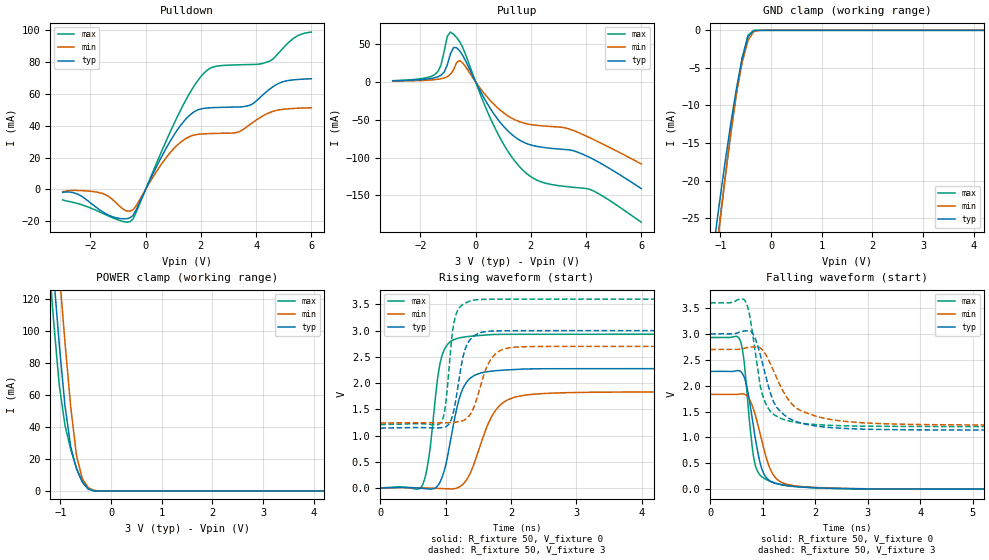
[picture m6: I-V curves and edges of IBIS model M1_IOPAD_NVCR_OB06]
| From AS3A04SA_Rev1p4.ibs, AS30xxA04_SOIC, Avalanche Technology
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[Model] M1_IOPAD_NVCR_OB06
Model_type I/O
Enable   Active-High
Vinl  =  0.9
Vinh  =  2.1
Vmeas =  1.5
Cref  =  30e-12
| Capacitance  typ   min   max
C_comp   3.872127e-12   3.590660e-12   4.190515e-12
| Variables   typ   min   max
[GND Clamp Reference]   0   0   0
[POWER Clamp Reference]   3   2.7   3.6
[Pulldown Reference]   0   0   0
[Pullup Reference]   3   2.7   3.6
[Temperature Range]   25   125   -40
[Voltage Range]   3   2.7   3.6
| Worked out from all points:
|   slope of the pulldown table from 0 to 0.45 V, typ, clamps not added: 27.9 ohm
|   slope of the pullup table from 0 to 0.45 V, typ, clamps not added: 14.9 ohm
|   GND clamp passes 1 mA (typ) near -0.46 V on its own axis
|   POWER clamp passes 1 mA (typ) near -0.42 V on its own axis
|   falling waveform, R_fixture 50, V_fixture 0: 20-80 % time 236ps typ, 304ps min, 174ps max; typ from 2.28 V to 0 V
|   falling waveform, R_fixture 50, V_fixture 3: 20-80 % time 382ps typ, 546ps min, 253ps max; typ from 3 V to 1.14 V
|   rising waveform, R_fixture 50, V_fixture 0: 20-80 % time 235ps typ, 350ps min, 166ps max; typ from 0 V to 2.28 V
|   rising waveform, R_fixture 50, V_fixture 3: 20-80 % time 164ps typ, 242ps min, 114ps max; typ from 1.14 V to 3 V
[GND Clamp]
| Voltage   I(typ)   I(min)   I(max)
-3V       -145.9mA   -153.7mA   -144.2mA
-1.138V   -29.07mA   -33.2mA    -32.68mA
-1.024V   -23.24mA   -26.38mA   -26.15mA
-910.3mV  -17.69mA   -19.83mA   -19.83mA
-796.6mV  -12.47mA   -13.74mA   -13.82mA
-682.8mV  -7.718mA   -8.413mA   -8.316mA
-569mV    -3.663mA   -4.215mA   -3.675mA
-455.2mV  -839.2uA   -1.36mA    -666.1uA
-341.4mV  -35.63uA   -163.9uA   -11.17uA
-113.8mV  -8.642nA   -411.9nA   -1.888nA
6V        0A         0A         0A
[POWER Clamp]
| Voltage   I(typ)   I(min)   I(max)
-3V       949.8mA    993.3mA    923.5mA
-1.252V   183.6mA    231.1mA    154mA
-1.138V   136.7mA    183.8mA    107.6mA
-1.024V   92.09mA    137.6mA    66.35mA
-910.3mV  53.33mA    93.06mA    41.06mA
-796.6mV  27.72mA    52.58mA    25.94mA
-682.8mV  13.75mA    22.15mA    14.29mA
-569mV    5.664mA    7.785mA    5.738mA
-455.2mV  1.446mA    2.116mA    1.305mA
-341.4mV  77.09uA    373.9uA    62.73uA
-227.6mV  1.148uA    21.11uA    332nA
6V        0A         0A         0A
[Pulldown]
| Voltage   I(typ)   I(min)   I(max)
-3V       -1.818mA   -1.414mA   -6.547mA
-2.39V    -3.494mA   -669uA     -9.164mA
-1.593V   -13.58mA   -2.334mA   -14.66mA
-569mV    -17.8mA    -13.62mA   -20.26mA
-341.4mV  -12.78mA   -10.3mA    -14.36mA
1.138V    37.05mA    27.66mA    45.21mA
2.069V    50.76mA    34.86mA    72.13mA
2.483V    51.35mA    35.13mA    76.98mA
3.745V    52.65mA    40.3mA     78.33mA
4.49V     62.91mA    48.21mA    80.49mA
5.359V    68.75mA    50.81mA    94.81mA
6V        69.43mA    51.26mA    98.69mA
[Pullup]
| Voltage   I(typ)   I(min)   I(max)
-3V       1.233mA    877.8uA    1.446mA
-1.479V   5.373mA    2.852mA    9.525mA
-1.252V   8.683mA    4.018mA    22.01mA
-1.138V   12.76mA    5.03mA     40.18mA
-910.3mV  37mA       9.541mA    65.62mA
-796.6mV  45.31mA    15.85mA    62.75mA
-569mV    40.45mA    27.87mA    52.57mA
724.1mV   -45.54mA   -31.9mA    -62.73mA
1.655V    -78.26mA   -53.49mA   -114.6mA
2.379V    -86.23mA   -58.05mA   -132.2mA
3.745V    -93.6mA    -67.38mA   -139.9mA
6V        -141mA     -108.5mA   -185.3mA
[Ramp]
dV/dt_r   1.36569/0.235041n  1.09954/0.350014n  1.75879/0.166379n
dV/dt_f   1.11466/0.381872n  0.876687/0.545945n  1.43365/0.253146n
R_load = 50
[Falling Waveform]
R_fixture = 50
V_fixture = 0
V_fixture_min = 0
V_fixture_max = 0
| Time   V(typ)   V(min)   V(max)
0s        2.276V     1.833V     2.931V
554.1ps   2.289V     1.838V     2.908V
626.6ps   2.209V     1.842V     2.606V
693ps     1.996V     1.809V     1.931V
801.9ps   1.342V     1.61V      787.8mV
880ps     855.4mV    1.351V     390.8mV
1.003ns   334.3mV    847.8mV    223.3mV
1.181ns   134.8mV    309.2mV    136.6mV
1.56ns    56.31mV    73.11mV    56.31mV
21.88ns   748.7nV    1.376uV    11.74uV
[Falling Waveform]
R_fixture = 50
V_fixture = 3
V_fixture_min = 2.7
V_fixture_max = 3.6
| Time   V(typ)   V(min)   V(max)
0s        3V         2.7V       3.6V
654.8ps   3.059V     2.729V     3.653V
737.2ps   3.06V      2.742V     3.421V
841.1ps   2.951V     2.749V     2.755V
956.6ps   2.58V      2.726V     1.976V
1.062ns   2.159V     2.593V     1.639V
1.276ns   1.567V     2.122V     1.4V
1.799ns   1.26V      1.488V     1.267V
3.916ns   1.146V     1.25V      1.212V
21.88ns   1.142V     1.239V     1.211V
[Rising Waveform]
R_fixture = 50
V_fixture = 0
V_fixture_min = 0
V_fixture_max = 0
| Time   V(typ)   V(min)   V(max)
0s        455.7nV    974.3nV    11.7uV
646.1ps   -3.297mV   7.37mV     61.69mV
745.3ps   -14.7mV    3.546mV    600.1mV
875.5ps   41.5mV     -3.001mV   2.072V
944.4ps   202.1mV    -6.768mV   2.525V
1.189ns   1.614V     11.34mV    2.854V
1.342ns   2.05V      202.5mV    2.888V
1.817ns   2.242V     1.561V     2.928V
2.464ns   2.274V     1.8V       2.93V
21.88ns   2.276V     1.833V     2.931V
[Rising Waveform]
R_fixture = 50
V_fixture = 3
V_fixture_min = 2.7
V_fixture_max = 3.6
| Time   V(typ)   V(min)   V(max)
0s        1.142V     1.239V     1.211V
928.5ps   1.15V      1.244V     1.248V
995.4ps   1.168V     1.244V     1.553V
1.099ns   1.352V     1.251V     2.914V
1.158ns   1.688V     1.258V     3.303V
1.29ns    2.611V     1.303V     3.517V
1.484ns   2.937V     1.734V     3.588V
1.741ns   2.992V     2.529V     3.598V
2.174ns   2.999V     2.692V     3.599V
21.88ns   3V         2.7V       3.6V
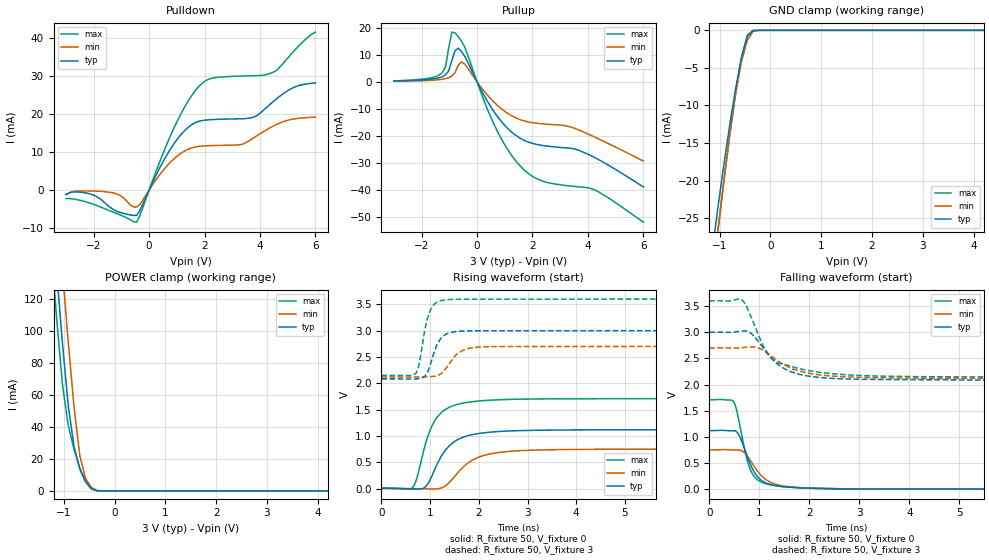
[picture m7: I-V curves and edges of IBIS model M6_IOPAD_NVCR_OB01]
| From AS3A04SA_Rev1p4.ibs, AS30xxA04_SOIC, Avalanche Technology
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[Model] M6_IOPAD_NVCR_OB01
Model_type I/O
Enable   Active-High
Vinl  =  0.9
Vinh  =  2.1
Vmeas =  1.5
Cref  =  30e-12
| Capacitance  typ   min   max
C_comp   3.872127e-12   3.590660e-12   4.190515e-12
| Variables   typ   min   max
[GND Clamp Reference]   0   0   0
[POWER Clamp Reference]   3   2.7   3.6
[Pulldown Reference]   0   0   0
[Pullup Reference]   3   2.7   3.6
[Temperature Range]   25   125   -40
[Voltage Range]   3   2.7   3.6
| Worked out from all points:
|   slope of the pulldown table from 0 to 0.45 V, typ, clamps not added: 66.9 ohm
|   slope of the pullup table from 0 to 0.45 V, typ, clamps not added: 53.1 ohm
|   GND clamp passes 1 mA (typ) near -0.46 V on its own axis
|   POWER clamp passes 1 mA (typ) near -0.42 V on its own axis
|   falling waveform, R_fixture 50, V_fixture 0: 20-80 % time 321ps typ, 404ps min, 255ps max; typ from 1.12 V to 0 V
|   falling waveform, R_fixture 50, V_fixture 3: 20-80 % time 599ps typ, 714ps min, 504ps max; typ from 3 V to 2.08 V
|   rising waveform, R_fixture 50, V_fixture 0: 20-80 % time 475ps typ, 578ps min, 386ps max; typ from 0 V to 1.12 V
|   rising waveform, R_fixture 50, V_fixture 3: 20-80 % time 221ps typ, 307ps min, 185ps max; typ from 2.08 V to 3 V
[GND Clamp]
| Voltage   I(typ)   I(min)   I(max)
-3V       -145.9mA   -153.7mA   -144.2mA
-1.138V   -29.07mA   -33.2mA    -32.68mA
-1.024V   -23.24mA   -26.38mA   -26.15mA
-910.3mV  -17.69mA   -19.83mA   -19.83mA
-796.6mV  -12.47mA   -13.74mA   -13.82mA
-682.8mV  -7.718mA   -8.413mA   -8.316mA
-569mV    -3.663mA   -4.215mA   -3.675mA
-455.2mV  -839.2uA   -1.36mA    -666.1uA
-341.4mV  -35.63uA   -163.9uA   -11.17uA
-113.8mV  -8.642nA   -411.9nA   -1.888nA
6V        0A         0A         0A
[POWER Clamp]
| Voltage   I(typ)   I(min)   I(max)
-3V       949.8mA    993.3mA    923.5mA
-1.252V   183.6mA    231.1mA    154mA
-1.138V   136.7mA    183.8mA    107.6mA
-1.024V   92.09mA    137.6mA    66.35mA
-910.3mV  53.33mA    93.06mA    41.06mA
-796.6mV  27.72mA    52.58mA    25.94mA
-682.8mV  13.75mA    22.15mA    14.29mA
-569mV    5.664mA    7.785mA    5.738mA
-455.2mV  1.446mA    2.116mA    1.305mA
-341.4mV  77.09uA    373.9uA    62.73uA
-227.6mV  1.148uA    21.11uA    332nA
6V        0A         0A         0A
[Pulldown]
| Voltage   I(typ)   I(min)   I(max)
-3V       -1.178mA   -1.235mA   -2.252mA
-2.162V   -950.8uA   -238uA     -3.362mA
-1.366V   -4.767mA   -675.5uA   -5.601mA
-455.2mV  -6.659mA   -4.469mA   -8.439mA
827.6mV   11.41mA    7.714mA    15.18mA
1.759V    17.96mA    11.42mA    26.89mA
2.276V    18.48mA    11.67mA    29.35mA
3.248V    18.68mA    11.86mA    29.88mA
3.745V    19.07mA    13.57mA    29.98mA
4.49V     23.28mA    16.82mA    30.94mA
5.234V    26.97mA    18.65mA    36.55mA
6V        28.1mA     19.13mA    41.44mA
[Pullup]
| Voltage   I(typ)   I(min)   I(max)
-3V       306.9uA    218.3uA    360.3uA
-1.366V   1.498mA    804.7uA    2.527mA
-1.138V   2.564mA    1.18mA     5.499mA
-1.024V   4.04mA     1.53mA     12.49mA
-910.3mV  7.819mA    2.112mA    18.38mA
-796.6mV  11.48mA    3.384mA    18.09mA
-455.2mV  9.605mA    6.652mA    13.03mA
620.7mV   -11.18mA   -7.609mA   -15.89mA
1.655V    -21.41mA   -14.32mA   -32.13mA
2.379V    -23.53mA   -15.54mA   -36.72mA
3.745V    -25.61mA   -18.1mA    -38.87mA
6V        -38.84mA   -29.27mA   -51.86mA
[Ramp]
dV/dt_r   0.671391/0.474616n  0.450443/0.578177n  1.02545/0.385509n
dV/dt_f   0.55145/0.59859n  0.348742/0.713857n  0.872156/0.50432n
R_load = 50
[Falling Waveform]
R_fixture = 50
V_fixture = 0
V_fixture_min = 0
V_fixture_max = 0
| Time   V(typ)   V(min)   V(max)
0s        1.119V     750.7mV    1.709V
473.4ps   1.118V     750mV      1.686V
533.2ps   1.106V     750.7mV    1.555V
593.2ps   1.034V     750.2mV    1.298V
728.9ps   703.6mV    668.5mV    653.8mV
863.5ps   386.6mV    484.9mV    288.7mV
1.084ns   142.2mV    217.9mV    117.2mV
1.528ns   42.92mV    54.51mV    43.77mV
3.632ns   1.461mV    2.02mV     1.096mV
21.88ns   384.8nV    1.042uV    8.699uV
[Falling Waveform]
R_fixture = 50
V_fixture = 3
V_fixture_min = 2.7
V_fixture_max = 3.6
| Time   V(typ)   V(min)   V(max)
0s        3V         2.7V       3.6V
657.7ps   3.026V     2.709V     3.615V
831.8ps   2.984V     2.72V      3.301V
1.084ns   2.691V     2.65V      2.73V
1.186ns   2.563V     2.583V     2.57V
1.324ns   2.424V     2.486V     2.441V
1.551ns   2.279V     2.351V     2.372V
1.808ns   2.194V     2.257V     2.302V
2.743ns   2.107V     2.147V     2.187V
21.88ns   2.081V     2.119V     2.146V
[Rising Waveform]
R_fixture = 50
V_fixture = 0
V_fixture_min = 0
V_fixture_max = 0
| Time   V(typ)   V(min)   V(max)
0s        324.6nV    979.6nV    8.69uV
624.3ps   -2.1mV     894.9uV    7.487mV
734.1ps   -6.735mV   -48.89uV   219.7mV
907.3ps   39.49mV    -2.876mV   860.6mV
1.128ns   434.2mV    -3.929mV   1.337V
1.475ns   879mV      201.2mV    1.575V
2.008ns   1.05V      601.2mV    1.666V
2.686ns   1.097V     712.4mV    1.696V
4.196ns   1.117V     746.6mV    1.708V
21.88ns   1.119V     750.7mV    1.709V
[Rising Waveform]
R_fixture = 50
V_fixture = 3
V_fixture_min = 2.7
V_fixture_max = 3.6
| Time   V(typ)   V(min)   V(max)
0s        2.081V     2.119V     2.146V
705ps     2.083V     2.12V      2.19V
773.5ps   2.089V     2.12V      2.37V
887.1ps   2.13V      2.12V      2.998V
1.012ns   2.382V     2.127V     3.402V
1.161ns   2.769V     2.152V     3.551V
1.364ns   2.948V     2.336V     3.59V
1.667ns   2.992V     2.624V     3.597V
2.253ns   2.999V     2.696V     3.599V
21.88ns   3V         2.7V       3.6V
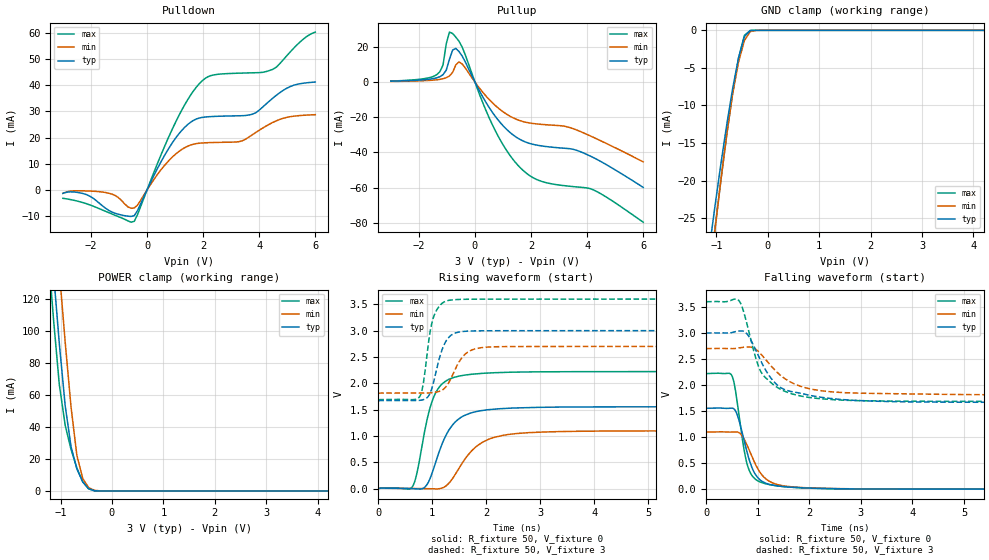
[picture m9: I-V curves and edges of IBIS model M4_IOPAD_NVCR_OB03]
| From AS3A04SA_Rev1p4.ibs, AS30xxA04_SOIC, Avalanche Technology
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[Model] M4_IOPAD_NVCR_OB03
Model_type I/O
Enable   Active-High
Vinl  =  0.9
Vinh  =  2.1
Vmeas =  1.5
Cref  =  30e-12
| Capacitance  typ   min   max
C_comp   3.872127e-12   3.590660e-12   4.190515e-12
| Variables   typ   min   max
[GND Clamp Reference]   0   0   0
[POWER Clamp Reference]   3   2.7   3.6
[Pulldown Reference]   0   0   0
[Pullup Reference]   3   2.7   3.6
[Temperature Range]   25   125   -40
[Voltage Range]   3   2.7   3.6
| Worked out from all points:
|   slope of the pulldown table from 0 to 0.45 V, typ, clamps not added: 46 ohm
|   slope of the pullup table from 0 to 0.45 V, typ, clamps not added: 34.5 ohm
|   GND clamp passes 1 mA (typ) near -0.46 V on its own axis
|   POWER clamp passes 1 mA (typ) near -0.42 V on its own axis
|   falling waveform, R_fixture 50, V_fixture 0: 20-80 % time 279ps typ, 355ps min, 219ps max; typ from 1.55 V to 0 V
|   falling waveform, R_fixture 50, V_fixture 3: 20-80 % time 543ps typ, 669ps min, 453ps max; typ from 3 V to 1.67 V
|   rising waveform, R_fixture 50, V_fixture 0: 20-80 % time 402ps typ, 532ps min, 297ps max; typ from 0 V to 1.55 V
|   rising waveform, R_fixture 50, V_fixture 3: 20-80 % time 219ps typ, 287ps min, 166ps max; typ from 1.67 V to 3 V
[GND Clamp]
| Voltage   I(typ)   I(min)   I(max)
-3V       -145.9mA   -153.7mA   -144.2mA
-1.138V   -29.07mA   -33.2mA    -32.68mA
-1.024V   -23.24mA   -26.38mA   -26.15mA
-910.3mV  -17.69mA   -19.83mA   -19.83mA
-796.6mV  -12.47mA   -13.74mA   -13.82mA
-682.8mV  -7.718mA   -8.413mA   -8.316mA
-569mV    -3.663mA   -4.215mA   -3.675mA
-455.2mV  -839.2uA   -1.36mA    -666.1uA
-341.4mV  -35.63uA   -163.9uA   -11.17uA
-113.8mV  -8.642nA   -411.9nA   -1.888nA
6V        0A         0A         0A
[POWER Clamp]
| Voltage   I(typ)   I(min)   I(max)
-3V       949.8mA    993.3mA    923.5mA
-1.252V   183.6mA    231.1mA    154mA
-1.138V   136.7mA    183.8mA    107.6mA
-1.024V   92.09mA    137.6mA    66.35mA
-910.3mV  53.33mA    93.06mA    41.06mA
-796.6mV  27.72mA    52.58mA    25.94mA
-682.8mV  13.75mA    22.15mA    14.29mA
-569mV    5.664mA    7.785mA    5.738mA
-455.2mV  1.446mA    2.116mA    1.305mA
-341.4mV  77.09uA    373.9uA    62.73uA
-227.6mV  1.148uA    21.11uA    332nA
6V        0A         0A         0A
[Pulldown]
| Voltage   I(typ)   I(min)   I(max)
-3V       -1.302mA   -1.27mA    -3.185mA
-2.162V   -1.762mA   -368.1uA   -5.24mA
-1.366V   -7.779mA   -1.22mA    -8.662mA
-455.2mV  -9.808mA   -6.881mA   -11.97mA
931mV     18.47mA    12.86mA    23.93mA
1.862V    27.49mA    17.86mA    40.59mA
2.379V    28.09mA    18.14mA    43.96mA
3.248V    28.34mA    18.4mA     44.61mA
3.745V    28.91mA    21.01mA    44.76mA
4.49V     35.12mA    25.83mA    46.12mA
5.11V     39.54mA    28.01mA    52.79mA
6V        41.23mA    28.76mA    60.32mA
[Pullup]
| Voltage   I(typ)   I(min)   I(max)
-3V       480.5uA    342.2uA    563.8uA
-1.366V   2.392mA    1.272mA    4.137mA
-1.138V   4.176mA    1.875mA    9.68mA
-910.3mV  12.91mA    3.392mA    28.39mA
-796.6mV  18.14mA    5.479mA    27.6mA
-455.2mV  14.74mA    10.29mA    19.83mA
620.7mV   -17.18mA   -11.77mA   -24.25mA
1.655V    -33.03mA   -22.19mA   -49.34mA
2.379V    -36.33mA   -24.08mA   -56.49mA
3.745V    -39.52mA   -28.03mA   -59.79mA
4.366V    -44.12mA   -32.49mA   -62.42mA
6V        -59.9mA    -45.37mA   -79.67mA
[Ramp]
dV/dt_r   0.931955/0.401817n  0.657846/0.531614n  1.33324/0.296908n
dV/dt_f   0.799473/0.543284n  0.533846/0.669445n  1.14844/0.452872n
R_load = 50
[Falling Waveform]
R_fixture = 50
V_fixture = 0
V_fixture_min = 0
V_fixture_max = 0
| Time   V(typ)   V(min)   V(max)
0s        1.553V     1.096V     2.222V
495.5ps   1.556V     1.096V     2.189V
543ps     1.539V     1.099V     2.038V
615.3ps   1.394V     1.095V     1.583V
731.8ps   952.6mV    971.5mV    780.2mV
838.4ps   555.3mV    743.6mV    354.5mV
949.5ps   291.5mV    492.9mV    196.4mV
1.107ns   137.6mV    245.4mV    116.8mV
1.489ns   50.53mV    65.65mV    50.77mV
21.88ns   478.9nV    1.117uV    10.18uV
[Falling Waveform]
R_fixture = 50
V_fixture = 3
V_fixture_min = 2.7
V_fixture_max = 3.6
| Time   V(typ)   V(min)   V(max)
0s        3V         2.7V       3.6V
625.8ps   3.037V     2.711V     3.633V
699.1ps   3.039V     2.723V     3.498V
813.3ps   2.956V     2.73V      3.087V
978.9ps   2.635V     2.675V     2.466V
1.092ns   2.4V       2.562V     2.205V
1.459ns   1.943V     2.174V     1.911V
2.195ns   1.77V      1.895V     1.738V
4.389ns   1.672V     1.824V     1.687V
21.88ns   1.668V     1.81V      1.686V
[Rising Waveform]
R_fixture = 50
V_fixture = 0
V_fixture_min = 0
V_fixture_max = 0
| Time   V(typ)   V(min)   V(max)
0s        382nV      969nV      10.07uV
614.8ps   -1.423mV   3.031mV    9.209mV
711ps     -7.837mV   1.452mV    263.7mV
872.8ps   33.79mV    -2.646mV   1.152V
1.07ns    516.4mV    -7.813mV   1.829V
1.361ns   1.187V     166.1mV    2.096V
1.693ns   1.428V     673mV      2.168V
2.267ns   1.517V     1.002V     2.205V
3.502ns   1.549V     1.085V     2.22V
21.88ns   1.553V     1.096V     2.222V
[Rising Waveform]
R_fixture = 50
V_fixture = 3
V_fixture_min = 2.7
V_fixture_max = 3.6
| Time   V(typ)   V(min)   V(max)
0s        1.668V     1.81V      1.686V
767.9ps   1.675V     1.812V     1.744V
837.4ps   1.689V     1.812V     2.007V
933.6ps   1.761V     1.815V     2.787V
1.032ns   2.045V     1.824V     3.278V
1.196ns   2.673V     1.877V     3.53V
1.389ns   2.938V     2.183V     3.587V
1.649ns   2.99V      2.585V     3.596V
2.153ns   2.998V     2.693V     3.599V
21.88ns   3V         2.7V       3.6V
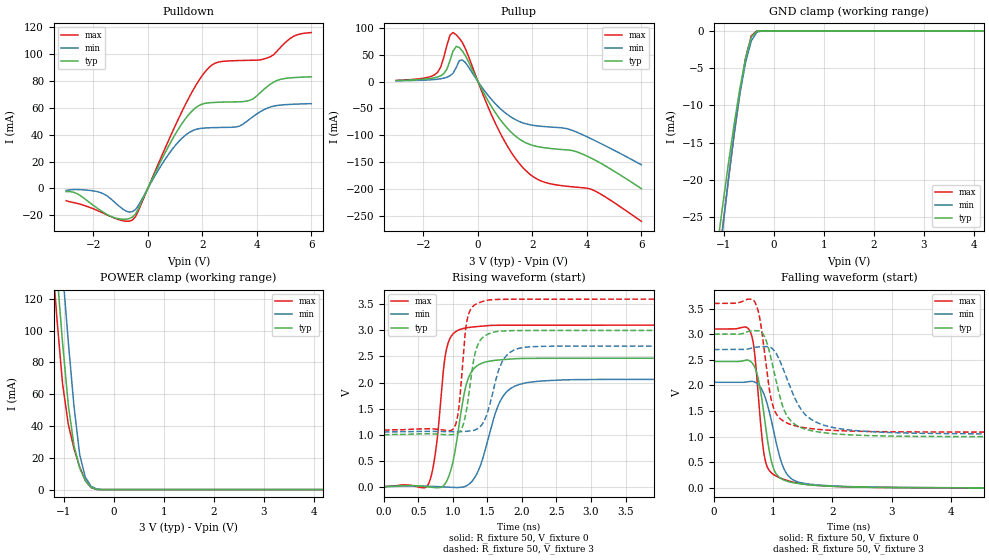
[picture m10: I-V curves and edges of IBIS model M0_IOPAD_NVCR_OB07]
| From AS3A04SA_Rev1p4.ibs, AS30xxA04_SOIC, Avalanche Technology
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[Model] M0_IOPAD_NVCR_OB07
Model_type I/O
Enable   Active-High
Vinl  =  0.9
Vinh  =  2.1
Vmeas =  1.5
Cref  =  30e-12
| Capacitance  typ   min   max
C_comp   3.872127e-12   3.590660e-12   4.190515e-12
| Variables   typ   min   max
[GND Clamp Reference]   0   0   0
[POWER Clamp Reference]   3   2.7   3.6
[Pulldown Reference]   0   0   0
[Pullup Reference]   3   2.7   3.6
[Temperature Range]   25   125   -40
[Voltage Range]   3   2.7   3.6
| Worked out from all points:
|   slope of the pulldown table from 0 to 0.45 V, typ, clamps not added: 23.6 ohm
|   slope of the pullup table from 0 to 0.45 V, typ, clamps not added: 10.6 ohm
|   GND clamp passes 1 mA (typ) near -0.46 V on its own axis
|   POWER clamp passes 1 mA (typ) near -0.42 V on its own axis
|   falling waveform, R_fixture 50, V_fixture 0: 20-80 % time 201ps typ, 270ps min, 152ps max; typ from 2.47 V to 0 V
|   falling waveform, R_fixture 50, V_fixture 3: 20-80 % time 290ps typ, 437ps min, 196ps max; typ from 3 V to 0.999 V
|   rising waveform, R_fixture 50, V_fixture 0: 20-80 % time 194ps typ, 288ps min, 142ps max; typ from 0 V to 2.47 V
|   rising waveform, R_fixture 50, V_fixture 3: 20-80 % time 142ps typ, 214ps min, 100ps max; typ from 0.999 V to 3 V
[GND Clamp]
| Voltage   I(typ)   I(min)   I(max)
-3V       -145.9mA   -153.7mA   -144.2mA
-1.138V   -29.07mA   -33.2mA    -32.68mA
-1.024V   -23.24mA   -26.38mA   -26.15mA
-910.3mV  -17.69mA   -19.83mA   -19.83mA
-796.6mV  -12.47mA   -13.74mA   -13.82mA
-682.8mV  -7.718mA   -8.413mA   -8.316mA
-569mV    -3.663mA   -4.215mA   -3.675mA
-455.2mV  -839.2uA   -1.36mA    -666.1uA
-341.4mV  -35.63uA   -163.9uA   -11.17uA
-113.8mV  -8.642nA   -411.9nA   -1.888nA
6V        0A         0A         0A
[POWER Clamp]
| Voltage   I(typ)   I(min)   I(max)
-3V       949.8mA    993.3mA    923.5mA
-1.252V   183.6mA    231.1mA    154mA
-1.138V   136.7mA    183.8mA    107.6mA
-1.024V   92.09mA    137.6mA    66.35mA
-910.3mV  53.33mA    93.06mA    41.06mA
-796.6mV  27.72mA    52.58mA    25.94mA
-682.8mV  13.75mA    22.15mA    14.29mA
-569mV    5.664mA    7.785mA    5.738mA
-455.2mV  1.446mA    2.116mA    1.305mA
-341.4mV  77.09uA    373.9uA    62.73uA
-227.6mV  1.148uA    21.11uA    332nA
6V        0A         0A         0A
[Pulldown]
| Voltage   I(typ)   I(min)   I(max)
-3V       -2.369mA   -1.543mA   -9.112mA
-1.707V   -16.78mA   -3.304mA   -17.73mA
-569mV    -21.4mA    -17.28mA   -23.59mA
1.138V    44.69mA    34.97mA    52.38mA
1.655V    58.29mA    43.12mA    72.96mA
2.172V    63.6mA     45.08mA    88.47mA
2.586V    64.15mA    45.36mA    94.06mA
3.372V    64.51mA    46.45mA    95.24mA
3.869V    66.73mA    53.57mA    95.46mA
4.366V    75.55mA    59.63mA    97.04mA
5.359V    82.53mA    62.72mA    113.4mA
6V        83.11mA    63.14mA    116.1mA
[Pullup]
| Voltage   I(typ)   I(min)   I(max)
-3V       1.852mA    1.317mA    2.173mA
-1.479V   8.502mA    4.354mA    17.23mA
-1.138V   23mA       7.89mA     67.38mA
-910.3mV  57.09mA    15.64mA    91.01mA
-796.6mV  65.16mA    26.12mA    86.79mA
-569mV    56.67mA    40.16mA    72.17mA
724.1mV   -64.02mA   -45.61mA   -86.41mA
1.759V    -113.8mA   -78.52mA   -165.6mA
2.483V    -123.4mA   -83.92mA   -187.7mA
3.745V    -132.9mA   -96.65mA   -197mA
4.366V    -147.8mA   -111.5mA   -205.2mA
6V        -199mA     -154.8mA   -259.8mA
[Ramp]
dV/dt_r   1.4802/0.19387n  1.23655/0.288455n  1.86079/0.142013n
dV/dt_f   1.2009/0.289582n  0.989594/0.437029n  1.5071/0.195569n
R_load = 50
[Falling Waveform]
R_fixture = 50
V_fixture = 0
V_fixture_min = 0
V_fixture_max = 0
| Time   V(typ)   V(min)   V(max)
0s        2.467V     2.061V     3.101V
597.5ps   2.482V     2.076V     3.078V
671.2ps   2.391V     2.073V     2.761V
748.6ps   2.115V     2.014V     1.781V
825.7ps   1.58V      1.876V     809mV
889.9ps   1.031V     1.668V     432.2mV
1.011ns   358.7mV    1.082V     254.9mV
1.18ns    151.8mV    373.8mV    164.1mV
1.518ns   69.13mV    88.54mV    73.8mV
21.88ns   1.03uV     1.656uV    12.78uV
[Falling Waveform]
R_fixture = 50
V_fixture = 3
V_fixture_min = 2.7
V_fixture_max = 3.6
| Time   V(typ)   V(min)   V(max)
0s        3V         2.7V       3.6V
671.7ps   3.068V     2.74V      3.659V
762.6ps   3.066V     2.753V     3.366V
854.8ps   2.947V     2.758V     2.625V
950.9ps   2.581V     2.746V     1.807V
1.04ns    2.132V     2.641V     1.468V
1.272ns   1.344V     2.007V     1.247V
1.756ns   1.092V     1.266V     1.141V
3.842ns   1.002V     1.06V      1.09V
21.88ns   998.5mV    1.051V     1.088V
[Rising Waveform]
R_fixture = 50
V_fixture = 0
V_fixture_min = 0
V_fixture_max = 0
| Time   V(typ)   V(min)   V(max)
0s        479.4nV    1.005uV    12.17uV
637.2ps   -181.3uV   12.37mV    33.92mV
757.3ps   -18.6mV    5.994mV    760.1mV
877.8ps   43.21mV    -2.21mV    2.419V
1ns       483.4mV    -10.92mV   2.932V
1.172ns   1.848V     6.517mV    3.044V
1.288ns   2.245V     127.9mV    3.066V
1.722ns   2.44V      1.73V      3.1V
2.285ns   2.466V     2.03V      3.1V
21.88ns   2.467V     2.061V     3.101V
[Rising Waveform]
R_fixture = 50
V_fixture = 3
V_fixture_min = 2.7
V_fixture_max = 3.6
| Time   V(typ)   V(min)   V(max)
0s        998.5mV    1.051V     1.088V
1.007ns   1.005V     1.057V     1.113V
1.085ns   1.044V     1.058V     1.514V
1.172ns   1.311V     1.062V     2.889V
1.22ns    1.675V     1.069V     3.281V
1.338ns   2.645V     1.104V     3.508V
1.532ns   2.943V     1.573V     3.586V
1.757ns   2.992V     2.491V     3.597V
2.209ns   2.999V     2.691V     3.599V
21.88ns   3V         2.7V       3.6V
